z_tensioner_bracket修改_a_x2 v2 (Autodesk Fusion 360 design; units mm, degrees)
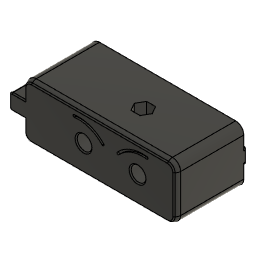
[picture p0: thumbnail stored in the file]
named bodies: "z_tensioner_bracket_a_x2"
